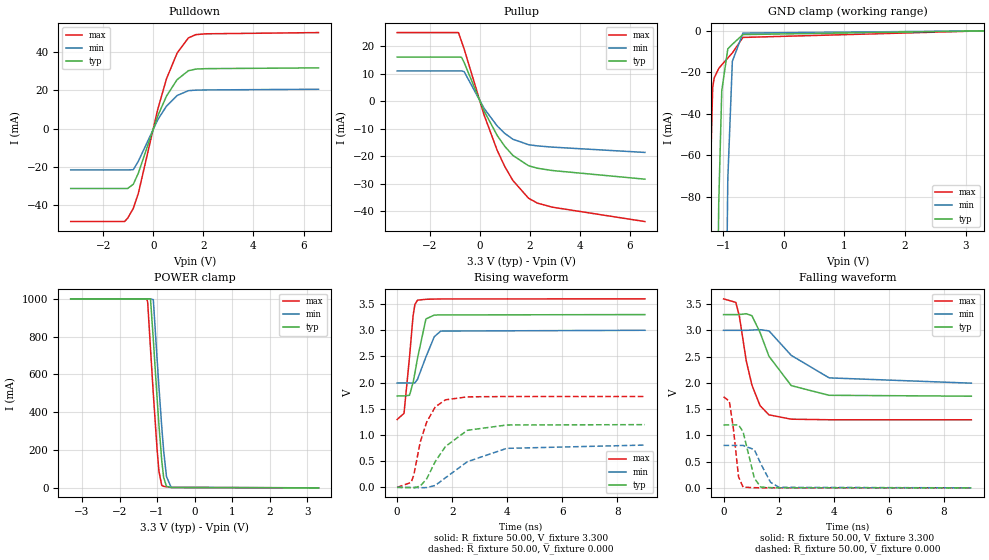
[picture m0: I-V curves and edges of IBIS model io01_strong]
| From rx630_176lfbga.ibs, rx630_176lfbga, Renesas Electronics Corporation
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[Model]   io01_strong
Model_type   I/O
Polarity   Non-Inverting
Enable   Active-High
Vinl  =   0.660V
Vinh  =   2.640V
Vmeas =   1.650V
Cref  =   30.00pF
| variable   typ   min   max
C_comp   5.910pF   5.910pF   5.910pF
| variable   typ   min   max
[Temperature Range]   45.000   105.000   -40.000
| variable   typ   min   max
[Voltage Range]   3.300V   3.000V   3.600V
| variable   typ   min   max
[Pullup Reference]   3.300V   3.000V   3.600V
| variable   typ   min   max
[Pulldown Reference]   0.000V   0.000V   0.000V
| variable   typ   min   max
[POWER Clamp Reference] 3.300V   3.000V   3.600V
| variable   typ   min   max
[GND Clamp Reference]   0.000V   0.000V   0.000V
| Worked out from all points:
|   slope of the pulldown table from 0 to 0.495 V, typ, clamps not added: 30.7 ohm
|   slope of the pullup table from 0 to 0.495 V, typ, clamps not added: 52.9 ohm
|   GND clamp passes 1 mA (typ) near -0.63 V on its own axis
|   POWER clamp passes 1 mA (typ) near -0.58 V on its own axis
|   rising waveform, R_fixture 50.00, V_fixture 3.300: 20-80 % time 321ps typ, 432ps min, 222ps max; typ from 1.75 V to 3.3 V
|   rising waveform, R_fixture 50.00, V_fixture 0.000: 20-80 % time 961ps typ, 1.48ns min, 553ps max; typ from 0 V to 1.2 V
|   falling waveform, R_fixture 50.00, V_fixture 3.300: 20-80 % time 902ps typ, 1.27ns min, 542ps max; typ from 3.3 V to 1.75 V
|   falling waveform, R_fixture 50.00, V_fixture 0.000: 20-80 % time 324ps typ, 446ps min, 218ps max; typ from 1.2 V to 0 V
[Pulldown]
| io01_strong Pulldown rx630
| Thu Mar 22 17:15:49 2012
| voltage   I(typ)   I(min)   I(max)
-3.3V     -31.31mA   -21.63mA   -48.57mA
-1.15V    -31.31mA   -21.63mA   -48.57mA
-1.025V   -31.31mA   -21.63mA   -46.81mA
-800mV    -29.1mA    -21.49mA   -41.71mA
-600mV    -23.34mA   -17.13mA   -33.95mA
175mV     6.49mA     4.538mA    9.911mA
525mV     16.92mA    11.68mA    25.93mA
950mV     25.49mA    17.23mA    39.38mA
1.4V      30.18mA    19.75mA    47.31mA
1.7V      31.04mA    20.05mA    49.02mA
2.1V      31.26mA    20.14mA    49.45mA
6.6V      31.67mA    20.5mA     50.09mA
[Pullup]
| io01_strong Pullup rx630
| Thu Mar 22 17:15:49 2012
| voltage   I(typ)   I(min)   I(max)
-3.3V     16.04mA    10.98mA    24.94mA
-850mV    16.04mA    10.98mA    24.94mA
-725mV    15.94mA    10.98mA    21.66mA
-625mV    14.1mA     10.75mA    19.05mA
175mV     -3.59mA    -2.649mA   -5.083mA
700mV     -12.53mA   -9.072mA   -17.96mA
1V        -16.45mA   -11.75mA   -23.79mA
1.325V    -19.76mA   -13.87mA   -28.89mA
1.95V     -23.51mA   -15.85mA   -35.33mA
2.3V      -24.41mA   -16.28mA   -37.1mA
2.9V      -25.25mA   -16.74mA   -38.59mA
6.6V      -28.4mA    -18.67mA   -43.82mA
[GND Clamp]
| io01_strong GNDClamp rx630
| Thu Mar 22 17:15:49 2012
| voltage   I(typ)   I(min)   I(max)
-3.3V     -1A        -1A        -1A
-1.325V   -1A        -1A        -369.2mA
-1.3V     -928.6mA   -1A        -269.7mA
-1.25V    -694.8mA   -1A        -112.6mA
-1.175V   -376mA     -953.3mA   -27.44mA
-1.15V    -283.8mA   -837.7mA   -22.69mA
-1.075V   -83.42mA   -512.2mA   -18.16mA
-1.025V   -28.94mA   -323mA     -16.39mA
-925mV    -8.707mA   -71.38mA   -13.1mA
-850mV    -6.468mA   -14.65mA   -10.64mA
-675mV    -1.81mA    -1.082mA   -3.186mA
3.3V      0A         0A         0A
[POWER Clamp]
| io01_strong PWRClamp rx630
| Thu Mar 22 17:15:49 2012
| voltage   I(typ)   I(min)   I(max)
-3.3V     1A         1A         1A
-1.275V   1A         1A         1A
-1.25V    1A         1A         982.1mA
-1.175V   1A         1A         736.6mA
-1.1V     784.3mA    995.9mA    498mA
-1V       476.2mA    683.1mA    204.7mA
-950mV    332.1mA    533mA      87.52mA
-875mV    143.3mA    321.7mA    12.76mA
-825mV    55.42mA    197.2mA    7.873mA
-750mV    8.12mA     59.94mA    5.513mA
-625mV    1.619mA    2.607mA    2.132mA
3.3V      0A         0A         0A
[Ramp]
dV/dt_r   0.719/960.74p  0.485/1.48n   1.041/552.35p
dV/dt_f   0.933/901.13p  0.604/1.27n   1.382/541.71p
R_load = 50.00ohm
[Rising Waveform]
| io01_strong Rising-High rx630
| Thu Mar 22 17:15:49 2012
R_fixture = 50.00
V_fixture = 3.300
V_fixture_min = 3.000
V_fixture_max = 3.600
C_fixture = 0.00pF
| Time   V(typ)   V(min)   V(max)
0s        1.746V     1.994V     1.297V
250ps     1.746V     1.994V     1.413V
450ps     1.759V     1.994V     2.489V
580ps     2.004V     1.989V     3.28V
645ps     2.183V     1.996V     3.491V
740ps     2.465V     2.064V     3.575V
1.045ns   3.216V     2.49V      3.592V
1.35ns    3.291V     2.878V     3.596V
1.585ns   3.293V     2.985V     3.598V
9ns       3.3V       3V         3.6V
[Rising Waveform]
| io01_strong Rising-Low rx630
| Thu Mar 22 17:15:49 2012
R_fixture = 50.00
V_fixture = 0.000
C_fixture = 0.00pF
| Time   V(typ)   V(min)   V(max)
0s        0V         0V         0V
510ps     -7mV       0V         95mV
605ps     -9mV       -1mV       236mV
840ps     25mV       -7mV       868mV
1.075ns   164mV      -4mV       1.25V
1.385ns   494mV      37mV       1.537V
1.755ns   781mV      183mV      1.672V
2.55ns    1.09V      490mV      1.729V
3.975ns   1.191V     745mV      1.735V
9ns       1.198V     808mV      1.735V
[Falling Waveform]
| io01_strong Falling-High rx630
| Thu Mar 22 17:15:49 2012
R_fixture = 50.00
V_fixture = 3.300
V_fixture_min = 3.000
V_fixture_max = 3.600
C_fixture = 0.00pF
| Time   V(typ)   V(min)   V(max)
0s        3.3V       3V         3.6V
445ps     3.3V       3V         3.533V
575ps     3.301V     3V         3.268V
825ps     3.317V     3V         2.418V
1.03ns    3.279V     3.006V     1.959V
1.325ns   2.961V     3.013V     1.567V
1.65ns    2.506V     2.99V      1.39V
2.46ns    1.947V     2.523V     1.308V
3.835ns   1.763V     2.095V     1.297V
9ns       1.746V     1.994V     1.297V
[Falling Waveform]
| io01_strong Falling-Low rx630
| Thu Mar 22 17:15:49 2012
R_fixture = 50.00
V_fixture = 0.000
C_fixture = 0.00pF
| Time   V(typ)   V(min)   V(max)
0s        1.198V     808mV      1.735V
210ps     1.198V     808mV      1.65V
350ps     1.198V     808mV      1.163V
545ps     1.199V     808mV      210mV
710ps     1.068V     808mV      13mV
1.12ns    182mV      727mV      3mV
1.35ns    15mV       460mV      1mV
1.71ns    4mV        104mV      1mV
2.015ns   2mV        10mV       0V
9ns       0V         0V         0V
